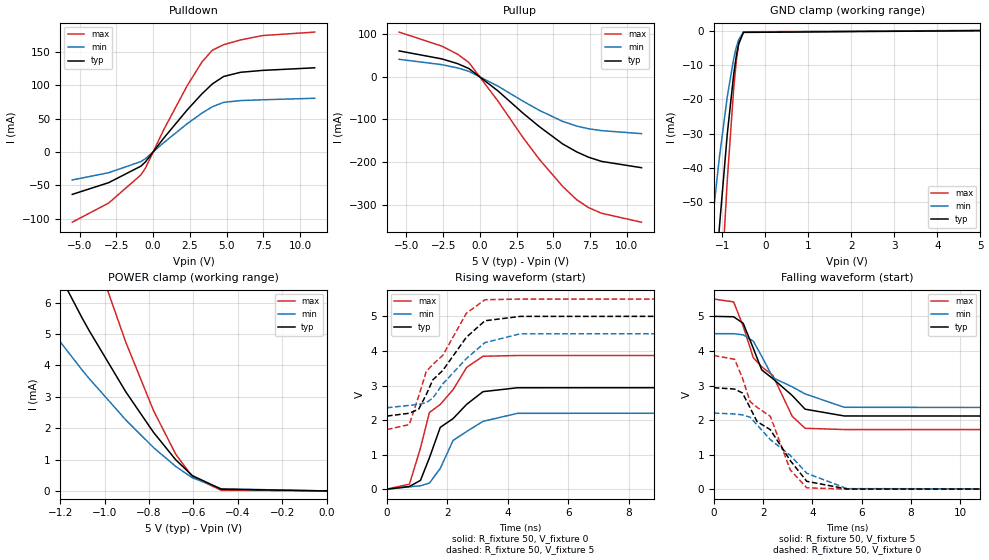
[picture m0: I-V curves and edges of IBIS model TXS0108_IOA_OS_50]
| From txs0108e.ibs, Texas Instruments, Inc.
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[Model]   TXS0108_IOA_OS_50
Model_type  I/O
Vinl=1.35
Vinh=3.85
Enable   Active-Low
Vref =   0
Rref =   1000000
Cref =   15p
Vmeas =   2.5
| variable   typ   min   max
C_comp   4.98pF   4.31pF   5.51pF
| C_pullup   4.44pF   3.65pF   5.60pF
| C_pulldown   5.24pF   4.78pF   5.57pF
| C_tri-state   4.98pF   4.31pF   5.51pF
[Temperature Range]   40   100   -40
| Ambient temperature   25   85   -40
[Voltage range]   5   4.5   5.5
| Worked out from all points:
|   slope of the pulldown table from 0 to 0.75 V, typ, clamps not added: 34.9 ohm
|   slope of the pullup table from 0 to 0.75 V, typ, clamps not added: 36.8 ohm
|   GND clamp passes 1 mA (typ) near -0.54 V on its own axis
|   POWER clamp passes 1 mA (typ) near -0.68 V on its own axis
|   rising waveform, R_fixture 50, V_fixture 0: 20-80 % time 1.24ns typ, 1.15ns min, 1.3ns max; typ from 0.002 V to 2.94 V
|   falling waveform, R_fixture 50, V_fixture 5: 20-80 % time 1.76ns typ, 1.85ns min, 1.74ns max; typ from 5 V to 2.12 V
|   rising waveform, R_fixture 50, V_fixture 5: 20-80 % time 1.37ns typ, 1.32ns min, 1.37ns max; typ from 2.12 V to 5 V
|   falling waveform, R_fixture 50, V_fixture 0: 20-80 % time 1.84ns typ, 1.97ns min, 1.75ns max; typ from 2.94 V to 0.002 V
[GND Clamp]
| TXS0108_IOA_OS_50
|   Voltage   I(typ)   I(min)   I(max)
-5.5V     -1.162A    -886.7mA   -1.457A
-1.485V   -135mA     -89.32mA   -194.3mA
-1.435V   -124.8mA   -82.28mA   -180.2mA
-1.23V    -85.21mA   -55.46mA   -124.7mA
-1.09V    -60.8mA    -39.25mA   -89.36mA
-1.065V   -56.7mA    -36.55mA   -83.34mA
-885mV    -30.02mA   -19.18mA   -43.38mA
-735mV    -12.53mA   -8.039mA   -16.57mA
-675mV    -7.294mA   -4.78mA    -8.768mA
-620mV    -3.741mA   -2.566mA   -3.881mA
-510mV    -503.4uA   -413.9uA   -323.1uA
5V        729.6pA    105.6uA    184.2pA
[POWER Clamp]
| TXS0108_IOA_OS_50
|   Voltage   I(typ)   I(min)   I(max)
-5.5V     90.64mA    62.18mA    150.4mA
-1.575V   12.3mA     8.412mA    20.42mA
-1.54V    11.75mA    8.047mA    19.49mA
-1.31V    8.334mA    5.751mA    13.61mA
-1.1V     5.493mA    3.841mA    8.726mA
-1.07V    5.113mA    3.585mA    8.074mA
-905mV    3.161mA    2.264mA    4.744mA
-780mV    1.867mA    1.382mA    2.561mA
-680mV    992.7uA    780.1uA    1.172mA
-605mV    486.5uA    418.6uA    452uA
-475mV    55.47uA    68.05uA    20.74uA
0V        0A         0A         0A
[Pulldown]
| TXS0108_IOA_OS_50
|   Voltage   I(typ)   I(min)   I(max)
-5.5V     -63.78mA   -42.12mA   -105.5mA
-3.02V    -46.14mA   -31.22mA   -76.72mA
-825mV    -21.34mA   -14.5mA    -34.47mA
-520mV    -15.06mA   -10.15mA   -24.4mA
715mV     20.4mA     13.71mA    32.88mA
2.325V    63.05mA    42.33mA    99.5mA
3.325V    87.1mA     58.2mA     134.8mA
4.03V     101.9mA    67.66mA    152.6mA
4.805V    113.2mA    74.38mA    160.9mA
5.965V    119.5mA    77.04mA    168.1mA
7.45V     122.3mA    78.2mA     174.6mA
11V       126.2mA    80.47mA    179.8mA
[Pullup]
| TXS0108_IOA_OS_50
|   Voltage   I(typ)   I(min)   I(max)
-5.5V     60.23mA    40.59mA    104.3mA
-2.605V   41.71mA    28.15mA    71.68mA
-1.52V    30.52mA    20.47mA    52.64mA
-745mV    18.91mA    12.58mA    32.97mA
1.24V     -33.61mA   -22.41mA   -57.58mA
2.92V     -85.01mA   -57.05mA   -141.8mA
4.035V    -116.6mA   -78.52mA   -193mA
5.635V    -157.4mA   -104.7mA   -256.8mA
6.595V    -176.1mA   -115.6mA   -288.1mA
7.395V    -188.5mA   -121.9mA   -306.4mA
8.29V     -198.3mA   -126.3mA   -319.7mA
11V       -213mA     -133.3mA   -340.5mA
[Ramp]
| TXS0108_IOA_OS_50
| variable   typ   min   max
dV/dt_r   1.76/1.25E-09   1.32/1.15E-09   2.32/1.30E-09
dV/dt_f   1.73/1.76E-09   1.29/1.86E-09   2.26/1.74E-09
R_load = 50
[Rising Waveform]
| TXS0108_IOA_OS_50
R_fixture =   50
C_fixture =   0
L_fixture =   0
V_fixture =   0
V_fixture_min = 0
V_fixture_max = 0
|   Time   V(typ)   V(min)   V(max)
0s        2.415mV    1.849mV    3.091mV
745ps     78.76mV    69.8mV     147.1mV
1.11ns    257.2mV    99.24mV    1.193V
1.405ns   906.8mV    177.7mV    2.22V
1.765ns   1.79V      602.8mV    2.452V
2.19ns    2.043V     1.412V     2.881V
2.64ns    2.456V     1.67V      3.525V
3.18ns    2.822V     1.964V     3.846V
4.325ns   2.935V     2.195V     3.868V
19.92ns   2.937V     2.203V     3.868V
[Falling Waveform]
| TXS0108_IOA_OS_50
R_fixture =   50
C_fixture =   0
L_fixture =   0
V_fixture =   5
V_fixture_min = 4.5
V_fixture_max = 5.5
|   Time   V(typ)   V(min)   V(max)
0s        5V         4.5V       5.5V
805ps     4.988V     4.498V     5.418V
1.195ns   4.798V     4.465V     4.713V
1.605ns   4.074V     4.283V     3.803V
1.945ns   3.452V     3.845V     3.542V
2.4ns     3.195V     3.225V     3.288V
3.18ns    2.712V     2.963V     2.112V
3.705ns   2.315V     2.757V     1.763V
5.295ns   2.119V     2.37V      1.726V
19.92ns   2.116V     2.357V     1.726V
[Rising Waveform]
| TXS0108_IOA_OS_50
R_fixture =   50
C_fixture =   0
L_fixture =   0
V_fixture =   5
V_fixture_min = 4.5
V_fixture_max = 5.5
|   Time   V(typ)   V(min)   V(max)
0s        2.116V     2.357V     1.726V
740ps     2.198V     2.425V     1.871V
1.05ns    2.315V     2.455V     2.689V
1.3ns     2.734V     2.502V     3.402V
1.52ns    3.165V     2.637V     3.611V
1.85ns    3.437V     3.048V     3.874V
2.63ns    4.396V     3.779V     5.091V
3.245ns   4.873V     4.242V     5.481V
4.415ns   4.999V     4.495V     5.5V
19.92ns   5V         4.5V       5.5V
[Falling Waveform]
| TXS0108_IOA_OS_50
R_fixture =   50
C_fixture =   0
L_fixture =   0
V_fixture =   0
V_fixture_min = 0
V_fixture_max = 0
|   Time   V(typ)   V(min)   V(max)
0s        2.937V     2.203V     3.868V
845ps     2.897V     2.176V     3.759V
1.165ns   2.783V     2.15V      3.212V
1.47ns    2.362V     2.084V     2.538V
1.755ns   1.957V     1.862V     2.37V
2.295ns   1.722V     1.435V     2.108V
3.105ns   827.4mV    978.5mV    556.9mV
3.775ns   228.6mV    460.9mV    40.84mV
5.41ns    6.523mV    17.31mV    3.988mV
19.92ns   2.417mV    1.85mV     3.092mV
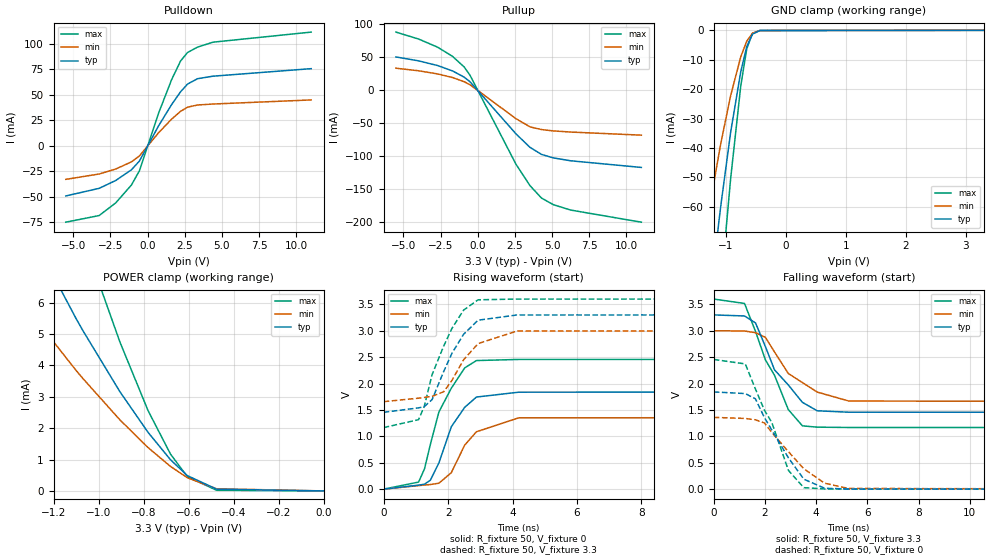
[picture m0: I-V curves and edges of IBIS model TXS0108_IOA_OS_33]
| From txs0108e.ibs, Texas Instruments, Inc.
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[Model]   TXS0108_IOA_OS_33
Model_type  I/O
Vinl=0.8
Vinh=2.0
Enable   Active-Low
Vref =   0
Rref =   1000000
Cref =   15p
Vmeas =   1.65
| variable   typ   min   max
C_comp   5.18pF   4.53pF   5.58pF
| C_pullup   4.70pF   3.82pF   5.92pF
| C_pulldown   5.52pF   5.09pF   5.94pF
| C_tri-state   5.18pF   4.53pF   5.58pF
[Temperature Range]   40   100   -40
| Ambient temperature   25   85   -40
[Voltage range]   3.3   3   3.6
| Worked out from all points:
|   slope of the pulldown table from 0 to 0.495 V, typ, clamps not added: 36.9 ohm
|   slope of the pullup table from 0 to 0.495 V, typ, clamps not added: 40 ohm
|   GND clamp passes 1 mA (typ) near -0.54 V on its own axis
|   POWER clamp passes 1 mA (typ) near -0.68 V on its own axis
|   rising waveform, R_fixture 50, V_fixture 0: 20-80 % time 779ps typ, 824ps min, 824ps max; typ from 0.002 V to 1.84 V
|   falling waveform, R_fixture 50, V_fixture 3.3: 20-80 % time 1.29ns typ, 1.53ns min, 1.23ns max; typ from 3.3 V to 1.46 V
|   rising waveform, R_fixture 50, V_fixture 3.3: 20-80 % time 869ps typ, 896ps min, 878ps max; typ from 1.46 V to 3.3 V
|   falling waveform, R_fixture 50, V_fixture 0: 20-80 % time 1.32ns typ, 1.54ns min, 1.21ns max; typ from 1.84 V to 0.002 V
[GND Clamp]
| TXS0108_IOA_OS_33
|   Voltage   I(typ)   I(min)   I(max)
-5.5V     -1.162A    -886.7mA   -1.457A
-1.485V   -135mA     -89.32mA   -194.3mA
-1.285V   -95.42mA   -62.32mA   -139.2mA
-1.24V    -87.04mA   -56.68mA   -127.3mA
-1.1V     -62.46mA   -40.34mA   -91.79mA
-1.08V    -59.15mA   -38.16mA   -86.94mA
-920mV    -34.79mA   -22.26mA   -50.61mA
-750mV    -14.03mA   -8.977mA   -18.85mA
-650mV    -5.516mA   -3.676mA   -6.254mA
-555mV    -1.279mA   -963.7uA   -1.023mA
-430mV    -72.15uA   -72.69uA   -27.98uA
3.3V      399.8pA    1.399uA    111.4pA
[POWER Clamp]
| TXS0108_IOA_OS_33
|   Voltage   I(typ)   I(min)   I(max)
-5.5V     90.64mA    62.18mA    150.4mA
-1.575V   12.3mA     8.412mA    20.42mA
-1.54V    11.75mA    8.047mA    19.49mA
-1.31V    8.334mA    5.751mA    13.61mA
-1.1V     5.493mA    3.841mA    8.726mA
-1.07V    5.113mA    3.585mA    8.074mA
-905mV    3.161mA    2.264mA    4.744mA
-780mV    1.867mA    1.382mA    2.561mA
-680mV    992.7uA    780.1uA    1.172mA
-605mV    486.5uA    418.6uA    452uA
-475mV    55.47uA    68.05uA    20.74uA
0V        0A         0A         0A
[Pulldown]
| TXS0108_IOA_OS_33
|   Voltage   I(typ)   I(min)   I(max)
-5.5V     -49.2mA    -32.91mA   -74.97mA
-3.255V   -41.72mA   -27.65mA   -68.43mA
-2.145V   -34.02mA   -22.77mA   -56.02mA
-1.09V    -23.56mA   -15.75mA   -38.51mA
-550mV    -14.93mA   -9.869mA   -24.48mA
735mV     19.58mA    12.8mA     32.01mA
1.615V    40.54mA    26.25mA    65.03mA
2.215V    53.05mA    33.87mA    83.29mA
2.68V     60.63mA    37.94mA    91.63mA
3.355V    65.93mA    40.11mA    96.94mA
4.395V    68.4mA     41.06mA    101.8mA
11V       75.8mA     45.09mA    111.7mA
[Pullup]
| TXS0108_IOA_OS_33
|   Voltage   I(typ)   I(min)   I(max)
-5.5V     50.72mA    33.63mA    88.38mA
-3.965V   44.75mA    29.7mA     77.77mA
-2.695V   37.64mA    24.95mA    65.49mA
-1.685V   29.4mA     19.4mA     51.39mA
-910mV    20.07mA    13.14mA    35.46mA
-520mV    13.1mA     8.58mA     22.93mA
2.57V     -65.87mA   -42.88mA   -111.9mA
3.51V     -86.32mA   -55.25mA   -144.3mA
4.285V    -97.02mA   -59.38mA   -163.2mA
5.08V     -102.3mA   -61.42mA   -173.2mA
6.245V    -106.7mA   -63.15mA   -181.4mA
11V       -116.8mA   -67.86mA   -199.8mA
[Ramp]
| TXS0108_IOA_OS_33
| variable   typ   min   max
dV/dt_r   1.10/7.83E-10   0.82/8.25E-10   1.47/8.28E-10
dV/dt_f   1.11/1.29E-09   0.81/1.53E-09   1.46/1.23E-09
R_load = 50
[Rising Waveform]
| TXS0108_IOA_OS_33
R_fixture =   50
C_fixture =   0
L_fixture =   0
V_fixture =   0
V_fixture_min = 0
V_fixture_max = 0
|   Time   V(typ)   V(min)   V(max)
0s        1.639mV    1.274mV    2.07mV
1.085ns   77.44mV    68.86mV    135.6mV
1.27ns    96.58mV    79.28mV    389.8mV
1.45ns    170.7mV    89.07mV    848.2mV
1.715ns   498.5mV    113.8mV    1.463V
2.1ns     1.183V     313.4mV    1.912V
2.515ns   1.55V      834.5mV    2.296V
2.88ns    1.745V     1.088V     2.436V
4.19ns    1.837V     1.351V     2.457V
19.95ns   1.842V     1.36V      2.457V
[Falling Waveform]
| TXS0108_IOA_OS_33
R_fixture =   50
C_fixture =   0
L_fixture =   0
V_fixture =   3.3
V_fixture_min = 3
V_fixture_max = 3.6
|   Time   V(typ)   V(min)   V(max)
0s        3.3V       3V         3.6V
1.2ns     3.28V      2.996V     3.517V
1.63ns    3.148V     2.963V     2.987V
2.015ns   2.701V     2.876V     2.45V
2.37ns    2.261V     2.599V     2.158V
2.91ns    1.974V     2.191V     1.508V
3.46ns    1.645V     2.019V     1.2V
4.04ns    1.485V     1.839V     1.175V
5.27ns    1.458V     1.67V      1.169V
19.95ns   1.456V     1.658V     1.167V
[Rising Waveform]
| TXS0108_IOA_OS_33
R_fixture =   50
C_fixture =   0
L_fixture =   0
V_fixture =   3.3
V_fixture_min = 3
V_fixture_max = 3.6
|   Time   V(typ)   V(min)   V(max)
0s        1.456V     1.658V     1.167V
1.085ns   1.54V      1.724V     1.317V
1.26ns    1.564V     1.737V     1.568V
1.505ns   1.698V     1.758V     2.172V
1.865ns   2.231V     1.846V     2.712V
2.12ns    2.573V     2.061V     3.045V
2.48ns    2.932V     2.449V     3.39V
2.93ns    3.2V       2.757V     3.586V
4.14ns    3.299V     2.995V     3.6V
19.95ns   3.3V       3V         3.6V
[Falling Waveform]
| TXS0108_IOA_OS_33
R_fixture =   50
C_fixture =   0
L_fixture =   0
V_fixture =   0
V_fixture_min = 0
V_fixture_max = 0
|   Time   V(typ)   V(min)   V(max)
0s        1.842V     1.36V      2.457V
1.23ns    1.811V     1.34V      2.372V
1.625ns   1.712V     1.314V     1.899V
1.98ns    1.354V     1.254V     1.493V
2.265ns   1.122V     1.075V     1.265V
2.915ns   594.1mV    710.6mV    355.7mV
3.515ns   190.6mV    387.4mV    29.92mV
4.33ns    17.96mV    113.2mV    5.557mV
5.26ns    5.019mV    14.81mV    2.72mV
19.95ns   1.64mV     1.275mV    2.071mV
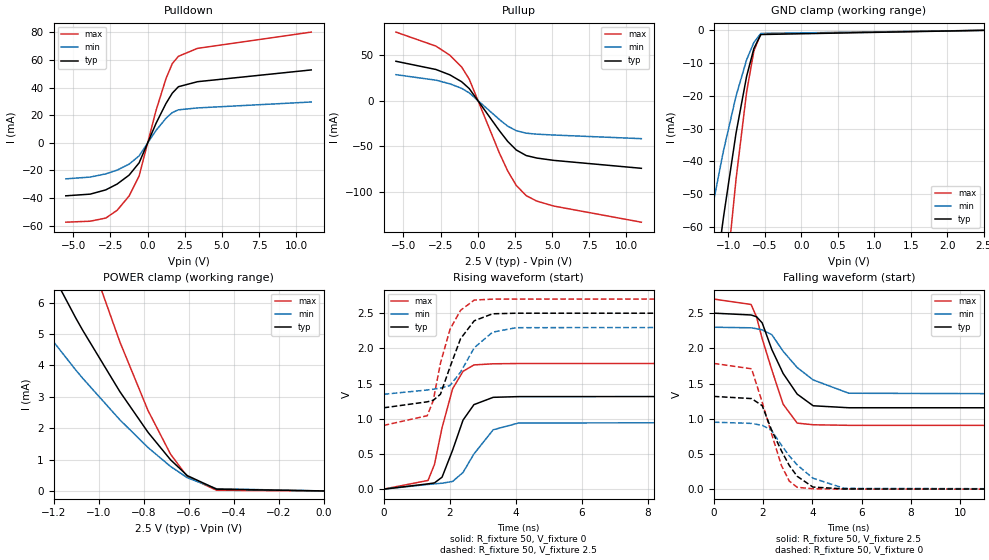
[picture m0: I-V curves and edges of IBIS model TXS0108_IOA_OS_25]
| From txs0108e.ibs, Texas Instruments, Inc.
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[Model]   TXS0108_IOA_OS_25
Model_type  I/O
Vinl=0.7
Vinh=1.7
Enable   Active-Low
Vref =   0
Rref =   1000000
Cref =   15p
Vmeas =   1.25
| variable   typ   min   max
C_comp   5.32pF   4.63pF   5.62pF
| C_pullup   5.03pF   3.89pF   6.32pF
| C_pulldown   5.75pF   5.36pF   6.43pF
| C_tri-state   5.32pF   4.63pF   5.62pF
[Temperature Range]   40   100   -40
| Ambient temperature   25   85   -40
[Voltage range]   2.5   2.3   2.7
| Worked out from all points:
|   slope of the pulldown table from 0 to 0.375 V, typ, clamps not added: 39.3 ohm
|   slope of the pullup table from 0 to 0.375 V, typ, clamps not added: 43.7 ohm
|   GND clamp passes 1 mA (typ) near -0.54 V on its own axis
|   POWER clamp passes 1 mA (typ) near -0.68 V on its own axis
|   rising waveform, R_fixture 50, V_fixture 0: 20-80 % time 608ps typ, 792ps min, 549ps max; typ from 0.001 V to 1.32 V
|   falling waveform, R_fixture 50, V_fixture 2.5: 20-80 % time 1.1ns typ, 1.55ns min, 932ps max; typ from 2.5 V to 1.16 V
|   rising waveform, R_fixture 50, V_fixture 2.5: 20-80 % time 643ps typ, 761ps min, 572ps max; typ from 1.16 V to 2.5 V
|   falling waveform, R_fixture 50, V_fixture 0: 20-80 % time 1.08ns typ, 1.38ns min, 888ps max; typ from 1.32 V to 0.001 V
[GND Clamp]
| TXS0108_IOA_OS_25
|   Voltage   I(typ)   I(min)   I(max)
-5.5V     -1.162A    -886.7mA   -1.457A
-1.475V   -132.9mA   -87.89mA   -191.4mA
-1.425V   -122.7mA   -80.89mA   -177.4mA
-1.235V   -86.12mA   -56.07mA   -126mA
-1.21V    -81.58mA   -53.03mA   -119.5mA
-1.085V   -59.97mA   -38.7mA    -88.15mA
-1.065V   -56.7mA    -36.55mA   -83.34mA
-895mV    -31.36mA   -20.04mA   -45.42mA
-750mV    -14.03mA   -8.977mA   -18.85mA
-650mV    -5.516mA   -3.676mA   -6.254mA
-555mV    -1.279mA   -963.7uA   -1.023mA
2.5V      289.1pA    97.72nA    83.51pA
[POWER Clamp]
| TXS0108_IOA_OS_25
|   Voltage   I(typ)   I(min)   I(max)
-5.5V     90.64mA    62.18mA    150.4mA
-1.575V   12.3mA     8.412mA    20.42mA
-1.54V    11.75mA    8.047mA    19.49mA
-1.31V    8.334mA    5.751mA    13.61mA
-1.1V     5.493mA    3.841mA    8.726mA
-1.07V    5.113mA    3.585mA    8.074mA
-905mV    3.161mA    2.264mA    4.744mA
-780mV    1.867mA    1.382mA    2.561mA
-680mV    992.7uA    780.1uA    1.172mA
-605mV    486.5uA    418.6uA    452uA
-475mV    55.47uA    68.05uA    20.74uA
0V        0A         0A         0A
[Pulldown]
| TXS0108_IOA_OS_25
|   Voltage   I(typ)   I(min)   I(max)
-5.5V     -38.38mA   -26.09mA   -57.48mA
-3.86V    -37.17mA   -24.81mA   -56.77mA
-2.81V    -34.07mA   -22.49mA   -54.48mA
-2.05V    -29.87mA   -19.76mA   -48.88mA
-1.245V   -23.41mA   -15.47mA   -38.52mA
-570mV    -14.49mA   -9.437mA   -23.98mA
565mV     14.07mA    8.957mA    23.39mA
1.24V     28.57mA    17.84mA    46.62mA
1.66V     35.97mA    21.9mA     57.39mA
2.07V     40.62mA    23.88mA    62.63mA
3.355V    44.26mA    25.26mA    68.41mA
11V       52.78mA    29.56mA    80.18mA
[Pullup]
| TXS0108_IOA_OS_25
|   Voltage   I(typ)   I(min)   I(max)
-5.5V     42.97mA    28.35mA    74.8mA
-2.81V    34mA       22.34mA    59.5mA
-1.87V    28.12mA    18.39mA    49.54mA
-1.085V   20.65mA    13.4mA     36.8mA
-575mV    13.25mA    8.569mA    23.58mA
1.455V    -32.73mA   -20.58mA   -57.12mA
2.02V     -44.58mA   -27.9mA    -76.88mA
2.59V     -53.81mA   -32.77mA   -92.47mA
3.255V    -59.87mA   -35.47mA   -103.6mA
3.97V     -62.63mA   -36.57mA   -109.6mA
5.11V     -65.15mA   -37.5mA    -115mA
11V       -73.81mA   -41.47mA   -132.6mA
[Ramp]
| TXS0108_IOA_OS_25
| variable   typ   min   max
dV/dt_r   0.79/6.09E-10   0.57/7.96E-10   1.07/5.55E-10
dV/dt_f   0.81/1.11E-09   0.57/1.55E-09   1.08/9.35E-10
R_load = 50
[Rising Waveform]
| TXS0108_IOA_OS_25
R_fixture =   50
C_fixture =   0
L_fixture =   0
V_fixture =   0
V_fixture_min = 0
V_fixture_max = 0
|   Time   V(typ)   V(min)   V(max)
0s        1.279mV    1.009mV    1.594mV
1.345ns   76.21mV    67.95mV    125mV
1.54ns    90.23mV    76.32mV    352.8mV
1.77ns    171.5mV    85.44mV    875.2mV
2.09ns    555.6mV    111mV      1.427V
2.405ns   981.5mV    238.2mV    1.674V
2.735ns   1.201V     500.6mV    1.765V
3.32ns    1.305V     844.6mV    1.781V
4.09ns    1.315V     940.3mV    1.785V
19.95ns   1.318V     951.8mV    1.786V
[Falling Waveform]
| TXS0108_IOA_OS_25
R_fixture =   50
C_fixture =   0
L_fixture =   0
V_fixture =   2.5
V_fixture_min = 2.3
V_fixture_max = 2.7
|   Time   V(typ)   V(min)   V(max)
0s        2.5V       2.3V       2.7V
1.515ns   2.474V     2.292V     2.623V
1.735ns   2.449V     2.279V     2.447V
1.965ns   2.362V     2.262V     2.138V
2.355ns   1.985V     2.195V     1.696V
2.815ns   1.644V     1.959V     1.208V
3.385ns   1.351V     1.728V     939.2mV
4.035ns   1.185V     1.552V     915.1mV
5.48ns    1.157V     1.363V     907.4mV
19.95ns   1.156V     1.348V     905.8mV
[Rising Waveform]
| TXS0108_IOA_OS_25
R_fixture =   50
C_fixture =   0
L_fixture =   0
V_fixture =   2.5
V_fixture_min = 2.3
V_fixture_max = 2.7
|   Time   V(typ)   V(min)   V(max)
0s        1.156V     1.348V     905.8mV
1.32ns    1.241V     1.409V     1.044V
1.5ns     1.262V     1.42V      1.254V
1.72ns    1.348V     1.436V     1.788V
2.01ns    1.734V     1.473V     2.27V
2.33ns    2.137V     1.662V     2.54V
2.745ns   2.392V     2.009V     2.686V
3.3ns     2.491V     2.23V      2.699V
4.02ns    2.499V     2.294V     2.7V
19.95ns   2.5V       2.3V       2.7V
[Falling Waveform]
| TXS0108_IOA_OS_25
R_fixture =   50
C_fixture =   0
L_fixture =   0
V_fixture =   0
V_fixture_min = 0
V_fixture_max = 0
|   Time   V(typ)   V(min)   V(max)
0s        1.318V     951.8mV    1.786V
1.535ns   1.287V     934.4mV    1.71V
1.965ns   1.187V     907.3mV    1.236V
2.33ns    854.7mV    842.7mV    807.1mV
2.745ns   545.9mV    627.4mV    337.6mV
3.065ns   337.7mV    474.3mV    116mV
3.385ns   184.1mV    345.3mV    27.82mV
4.025ns   30.96mV    156.6mV    6.487mV
5.295ns   4.435mV    12.47mV    2.133mV
19.95ns   1.279mV    1.01mV     1.595mV
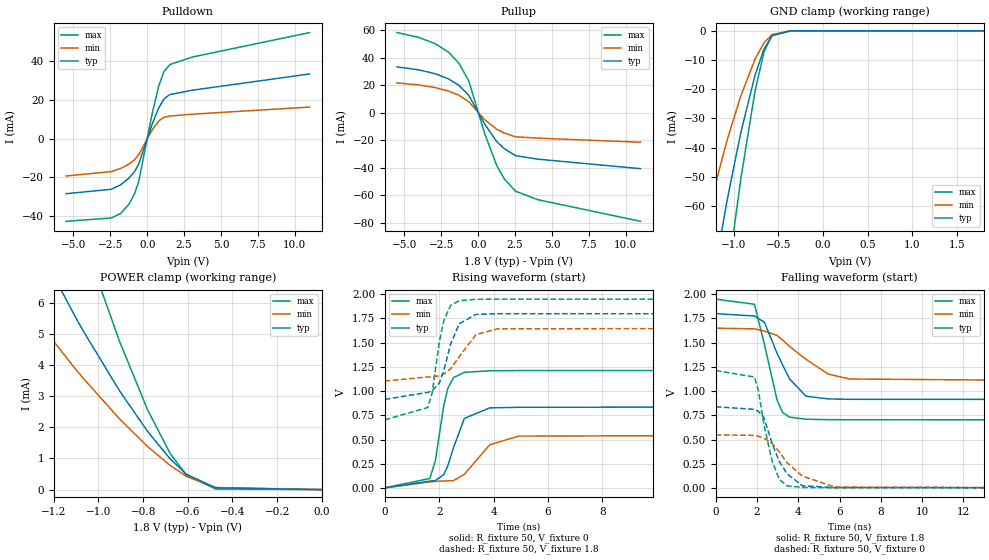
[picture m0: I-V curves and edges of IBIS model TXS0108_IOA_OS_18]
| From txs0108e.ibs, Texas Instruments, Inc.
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[Model]   TXS0108_IOA_OS_18
Model_type  I/O
Vinl=0.5775
Vinh=1.2675
Enable   Active-Low
Vref =   0
Rref =   1000000
Cref =   15p
Vmeas =   0.9
| variable   typ   min   max
C_comp   5.46pF   4.75pF   5.78pF
| C_pullup   5.54pF   4.12pF   6.50pF
| C_pulldown   6.05pF   5.46pF   6.99pF
| C_tri-state   5.46pF   4.75pF   5.78pF
[Temperature Range]   40   100   -40
| Ambient temperature   25   85   -40
[Voltage range]   1.8   1.65   1.95
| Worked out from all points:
|   slope of the pulldown table from 0 to 0.27 V, typ, clamps not added: 44.3 ohm
|   slope of the pullup table from 0 to 0.27 V, typ, clamps not added: 51.5 ohm
|   GND clamp passes 1 mA (typ) near -0.54 V on its own axis
|   POWER clamp passes 1 mA (typ) near -0.68 V on its own axis
|   rising waveform, R_fixture 50, V_fixture 0: 20-80 % time 606ps typ, 1.01ns min, 427ps max; typ from 0.001 V to 0.838 V
|   falling waveform, R_fixture 50, V_fixture 1.8: 20-80 % time 1.12ns typ, 1.96ns min, 765ps max; typ from 1.8 V to 0.914 V
|   rising waveform, R_fixture 50, V_fixture 1.8: 20-80 % time 579ps typ, 829ps min, 421ps max; typ from 0.914 V to 1.8 V
|   falling waveform, R_fixture 50, V_fixture 0: 20-80 % time 939ps typ, 1.46ns min, 679ps max; typ from 0.838 V to 0.001 V
[GND Clamp]
| TXS0108_IOA_OS_18
|   Voltage   I(typ)   I(min)   I(max)
-5.5V     -1.162A    -886.7mA   -1.457A
-1.485V   -135mA     -89.32mA   -194.3mA
-1.435V   -124.8mA   -82.28mA   -180.2mA
-1.225V   -84.3mA    -54.85mA   -123.4mA
-1.085V   -59.97mA   -38.7mA    -88.15mA
-1.065V   -56.7mA    -36.55mA   -83.34mA
-920mV    -34.79mA   -22.26mA   -50.61mA
-760mV    -15.06mA   -9.626mA   -20.43mA
-660mV    -6.196mA   -4.099mA   -7.202mA
-570mV    -1.688mA   -1.24mA    -1.444mA
-365mV    -12.15uA   -15.38uA   -2.755uA
1.8V      209pA      23.51nA    59.06pA
[POWER Clamp]
| TXS0108_IOA_OS_18
|   Voltage   I(typ)   I(min)   I(max)
-5.5V     90.64mA    62.18mA    150.4mA
-1.575V   12.3mA     8.412mA    20.42mA
-1.54V    11.75mA    8.047mA    19.49mA
-1.31V    8.334mA    5.751mA    13.61mA
-1.1V     5.493mA    3.841mA    8.726mA
-1.07V    5.113mA    3.585mA    8.074mA
-905mV    3.161mA    2.264mA    4.744mA
-780mV    1.867mA    1.382mA    2.561mA
-680mV    992.7uA    780.1uA    1.172mA
-605mV    486.5uA    418.6uA    452uA
-475mV    55.47uA    68.05uA    20.74uA
0V        0A         0A         0A
[Pulldown]
| TXS0108_IOA_OS_18
|   Voltage   I(typ)   I(min)   I(max)
-5.5V     -28.43mA   -19.26mA   -42.65mA
-2.425V   -26.12mA   -17.02mA   -40.94mA
-1.795V   -23.8mA    -15.4mA    -38.63mA
-1.245V   -20.46mA   -13.17mA   -33.93mA
-855mV    -17.03mA   -10.89mA   -28.4mA
-575mV    -13.17mA   -8.336mA   -22.18mA
325mV     7.229mA    4.354mA    12.46mA
790mV     15.97mA    9.139mA    27.36mA
1.14V     20.45mA    11.03mA    34.57mA
1.535V    22.71mA    11.65mA    38.18mA
3.05V     24.95mA    12.58mA    42.06mA
11V       33.34mA    16.28mA    54.69mA
[Pullup]
| TXS0108_IOA_OS_18
|   Voltage   I(typ)   I(min)   I(max)
-5.5V     33.3mA     21.65mA    58.23mA
-4.06V    31.21mA    20.21mA    54.85mA
-2.92V    28.35mA    18.27mA    50.19mA
-2.005V   24.56mA    15.74mA    43.93mA
-1.3V     19.87mA    12.66mA    35.91mA
-630mV    12.55mA    7.934mA    22.85mA
430mV     -8.16mA    -5.025mA   -14.85mA
1.265V    -21.13mA   -12.09mA   -38.67mA
1.775V    -26.2mA    -14.78mA   -48.17mA
2.53V     -31.21mA   -17.53mA   -57.04mA
4.03V     -33.73mA   -18.47mA   -63.18mA
11V       -40.66mA   -21.47mA   -78.9mA
[Ramp]
| TXS0108_IOA_OS_18
| variable   typ   min   max
dV/dt_r   0.50/6.13E-10   0.33/1.01E-09   0.73/4.32E-10
dV/dt_f   0.53/1.12E-09   0.33/1.96E-09   0.75/7.66E-10
R_load = 50
[Rising Waveform]
| TXS0108_IOA_OS_18
R_fixture =   50
C_fixture =   0
L_fixture =   0
V_fixture =   0
V_fixture_min = 0
V_fixture_max = 0
|   Time   V(typ)   V(min)   V(max)
0s        969.5uV    766.9uV    1.205mV
1.655ns   70.4mV     61.67mV    97.38mV
1.86ns    76.46mV    66.92mV    280.3mV
2.165ns   136.8mV    71.67mV    844.1mV
2.315ns   227mV      72.56mV    1.026V
2.525ns   414.1mV    75.81mV    1.139V
2.925ns   717.8mV    139.6mV    1.194V
3.86ns    826.8mV    446.2mV    1.21V
4.93ns    832.8mV    535.1mV    1.212V
19.95ns   838.2mV    547.6mV    1.213V
[Falling Waveform]
| TXS0108_IOA_OS_18
R_fixture =   50
C_fixture =   0
L_fixture =   0
V_fixture =   1.8
V_fixture_min = 1.65
V_fixture_max = 1.95
|   Time   V(typ)   V(min)   V(max)
0s        1.8V       1.65V      1.95V
1.87ns    1.776V     1.643V     1.897V
2.355ns   1.711V     1.62V      1.483V
2.965ns   1.393V     1.575V     911.7mV
3.235ns   1.272V     1.528V     780mV
3.57ns    1.127V     1.462V     731.2mV
4.37ns    947.7mV    1.328V     709.6mV
5.45ns    919.3mV    1.176V     705.1mV
6.495ns   915.4mV    1.125V     704.5mV
19.95ns   914.1mV    1.104V     703.4mV
[Rising Waveform]
| TXS0108_IOA_OS_18
R_fixture =   50
C_fixture =   0
L_fixture =   0
V_fixture =   1.8
V_fixture_min = 1.65
V_fixture_max = 1.95
|   Time   V(typ)   V(min)   V(max)
0s        914.1mV    1.104V     703.4mV
1.58ns    987.2mV    1.146V     830.3mV
1.745ns   1.004V     1.148V     985.6mV
2.005ns   1.083V     1.158V     1.51V
2.175ns   1.219V     1.177V     1.733V
2.425ns   1.49V      1.232V     1.887V
2.74ns    1.696V     1.357V     1.934V
3.355ns   1.792V     1.583V     1.948V
4.14ns    1.799V     1.643V     1.95V
19.95ns   1.8V       1.65V      1.95V
[Falling Waveform]
| TXS0108_IOA_OS_18
R_fixture =   50
C_fixture =   0
L_fixture =   0
V_fixture =   0
V_fixture_min = 0
V_fixture_max = 0
|   Time   V(typ)   V(min)   V(max)
0s        838.3mV    547.6mV    1.213V
1.87ns    811.5mV    543.1mV    1.146V
2.07ns    789.5mV    533.4mV    1V
2.33ns    727.1mV    511.8mV    655.9mV
2.725ns   460.3mV    459.6mV    278.5mV
3.08ns    273.3mV    370.2mV    88.19mV
3.445ns   148.6mV    262.5mV    21.63mV
4.19ns    22.91mV    123.4mV    5.242mV
5.75ns    3.308mV    9.794mV    1.599mV
19.95ns   969.7uV    767.9uV    1.205mV
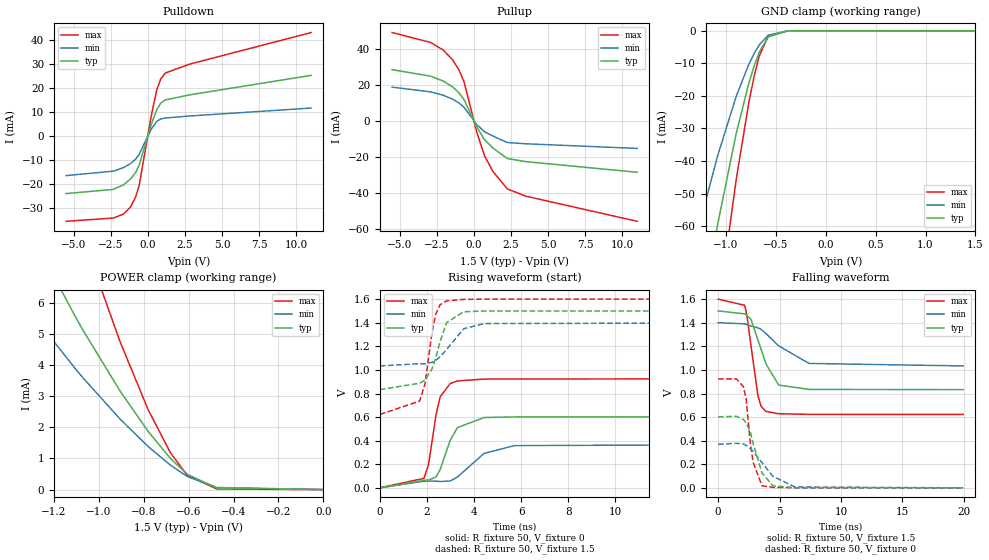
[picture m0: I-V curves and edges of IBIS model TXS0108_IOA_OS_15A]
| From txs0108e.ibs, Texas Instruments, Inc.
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[Model]   TXS0108_IOA_OS_15A
Model_type  I/O
Vinl=0.15
Vinh=1.4
Enable   Active-Low
Vref =   0
Rref =   1000000
Cref =   15p
Vmeas =   0.75
| variable   typ   min   max
C_comp   5.53pF   4.82pF   5.86pF
| C_pullup   5.82pF   4.31pF   6.75pF
| C_pulldown   6.22pF   5.50pF   7.19pF
| C_tri-state   5.53pF   4.82pF   5.86pF
[Temperature Range]   40   100   -40
| Ambient temperature   25   85   -40
[Voltage range]   1.5   1.4   1.6
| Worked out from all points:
|   slope of the pulldown table from 0 to 0.225 V, typ, clamps not added: 48.9 ohm
|   slope of the pullup table from 0 to 0.225 V, typ, clamps not added: 59 ohm
|   GND clamp passes 1 mA (typ) near -0.54 V on its own axis
|   POWER clamp passes 1 mA (typ) near -0.68 V on its own axis
|   rising waveform, R_fixture 50, V_fixture 0: 20-80 % time 708ps typ, 1.29ns min, 457ps max; typ from 0.001 V to 0.602 V
|   falling waveform, R_fixture 50, V_fixture 1.5: 20-80 % time 1.31ns typ, 2.31ns min, 750ps max; typ from 1.5 V to 0.833 V
|   rising waveform, R_fixture 50, V_fixture 1.5: 20-80 % time 647ps typ, 886ps min, 441ps max; typ from 0.833 V to 1.5 V
|   falling waveform, R_fixture 50, V_fixture 0: 20-80 % time 1ns typ, 1.76ns min, 616ps max; typ from 0.602 V to 0.001 V
[GND Clamp]
| TXS0108_IOA_OS_15A
|   Voltage   I(typ)   I(min)   I(max)
-5.5V     -1.162A    -886.7mA   -1.457A
-1.47V    -131.9mA   -87.19mA   -190mA
-1.42V    -121.7mA   -80.21mA   -176mA
-1.24V    -87.04mA   -56.68mA   -127.3mA
-1.08V    -59.15mA   -38.16mA   -86.94mA
-895mV    -31.36mA   -20.04mA   -45.42mA
-770mV    -16.12mA   -10.3mA    -22.07mA
-715mV    -10.65mA   -6.862mA   -13.72mA
-665mV    -6.551mA   -4.319mA   -7.705mA
-575mV    -1.844mA   -1.344mA   -1.612mA
-380mV    -18.61uA   -22.23uA   -4.813uA
1.5V      178.6pA    5.585nA    50.12pA
[POWER Clamp]
| TXS0108_IOA_OS_15A
|   Voltage   I(typ)   I(min)   I(max)
-5.5V     90.64mA    62.18mA    150.4mA
-1.575V   12.3mA     8.412mA    20.42mA
-1.54V    11.75mA    8.047mA    19.49mA
-1.31V    8.334mA    5.751mA    13.61mA
-1.1V     5.493mA    3.841mA    8.726mA
-1.07V    5.113mA    3.585mA    8.074mA
-905mV    3.161mA    2.264mA    4.744mA
-780mV    1.867mA    1.382mA    2.561mA
-680mV    992.7uA    780.1uA    1.172mA
-605mV    486.5uA    418.6uA    452uA
-475mV    55.47uA    68.05uA    20.74uA
0V        0A         0A         0A
[Pulldown]
| TXS0108_IOA_OS_15A
|   Voltage   I(typ)   I(min)   I(max)
-5.5V     -24.12mA   -16.6mA    -35.69mA
-2.325V   -22.36mA   -14.74mA   -34.33mA
-1.64V    -20.5mA    -13.28mA   -32.7mA
-1.165V   -18.06mA   -11.58mA   -29.76mA
-825mV    -15.38mA   -9.784mA   -25.66mA
-575mV    -12.21mA   -7.667mA   -20.64mA
225mV     4.564mA    2.68mA     8.031mA
600mV     10.84mA    6.024mA    19.01mA
875mV     13.67mA    7.085mA    23.84mA
1.18V     15.01mA    7.457mA    26.26mA
2.84V     17.16mA    8.314mA    30.01mA
11V       25.27mA    11.62mA    43.16mA
[Pullup]
| TXS0108_IOA_OS_15A
|   Voltage   I(typ)   I(min)   I(max)
-5.5V     28.3mA     18.62mA    48.86mA
-2.91V    24.7mA     16.02mA    43.4mA
-2.05V    21.98mA    14.13mA    39.14mA
-1.405V   18.64mA    11.89mA    33.59mA
-985mV    15.35mA    9.747mA    27.96mA
-655mV    11.77mA    7.443mA    21.53mA
210mV     -3.572mA   -2.197mA   -6.546mA
725mV     -10.5mA    -6.079mA   -19.47mA
1.29V     -15.12mA   -8.495mA   -28.09mA
2.255V    -20.92mA   -12.05mA   -37.72mA
3.49V     -22.62mA   -12.75mA   -41.75mA
11V       -28.54mA   -15.31mA   -55.69mA
[Ramp]
| TXS0108_IOA_OS_15A
| variable   typ   min   max
dV/dt_r   0.36/7.10E-10   0.22/1.29E-09   0.55/4.60E-10
dV/dt_f   0.40/1.31E-09   0.22/2.31E-09   0.59/7.54E-10
R_load = 50
[Rising Waveform]
| TXS0108_IOA_OS_15A
R_fixture =   50
C_fixture =   0
L_fixture =   0
V_fixture =   0
V_fixture_min = 0
V_fixture_max = 0
|   Time   V(typ)   V(min)   V(max)
0s        840.5uV    675.3uV    1.03mV
1.875ns   64.87mV    57.08mV    81.37mV
2.07ns    67.27mV    58.79mV    200.3mV
2.385ns   92.89mV    57.38mV    617.5mV
2.56ns    155.3mV    54.73mV    771.5mV
2.99ns    405mV      59.01mV    884.9mV
3.295ns   511mV      92.29mV    906.7mV
4.425ns   596.7mV    292.4mV    922.6mV
5.725ns   601.8mV    358.9mV    923.4mV
19.95ns   602.5mV    369.4mV    924.2mV
[Falling Waveform]
| TXS0108_IOA_OS_15A
R_fixture =   50
C_fixture =   0
L_fixture =   0
V_fixture =   1.5
V_fixture_min = 1.4
V_fixture_max = 1.6
|   Time   V(typ)   V(min)   V(max)
0s        1.5V       1.4V       1.6V
2.16ns    1.475V     1.391V     1.548V
2.345ns   1.463V     1.384V     1.461V
2.675ns   1.428V     1.372V     1.205V
3.235ns   1.256V     1.357V     784.8mV
3.495ns   1.176V     1.344V     691.4mV
3.9ns     1.05V      1.308V     648.3mV
4.925ns   871.6mV    1.204V     628.9mV
7.41ns    834.8mV    1.055V     623.4mV
19.95ns   833.2mV    1.034V     623mV
[Rising Waveform]
| TXS0108_IOA_OS_15A
R_fixture =   50
C_fixture =   0
L_fixture =   0
V_fixture =   1.5
V_fixture_min = 1.4
V_fixture_max = 1.6
|   Time   V(typ)   V(min)   V(max)
0s        833.2mV    1.034V     622.8mV
1.69ns    887.5mV    1.053V     735.7mV
1.92ns    914.3mV    1.052V     881.6mV
2.21ns    1.007V     1.064V     1.309V
2.365ns   1.094V     1.08V      1.467V
2.55ns    1.234V     1.109V     1.551V
2.835ns   1.401V     1.174V     1.585V
3.565ns   1.493V     1.349V     1.598V
4.43ns    1.499V     1.393V     1.6V
19.95ns   1.5V       1.4V       1.6V
[Falling Waveform]
| TXS0108_IOA_OS_15A
R_fixture =   50
C_fixture =   0
L_fixture =   0
V_fixture =   0
V_fixture_min = 0
V_fixture_max = 0
|   Time   V(typ)   V(min)   V(max)
0s        602.5mV    369.4mV    924.2mV
1.485ns   607mV      378.4mV    924.9mV
2.065ns   580mV      372.8mV    856.5mV
2.28ns    551.6mV    361.4mV    752.5mV
2.62ns    475.4mV    333.1mV    381.4mV
2.85ns    377.2mV    309.9mV    217.5mV
3.57ns    127.7mV    215.4mV    18.42mV
4.455ns   17.92mV    98.41mV    4.64mV
6.245ns   2.193mV    8.689mV    1.406mV
19.95ns   840.7uV    678uV      1.03mV
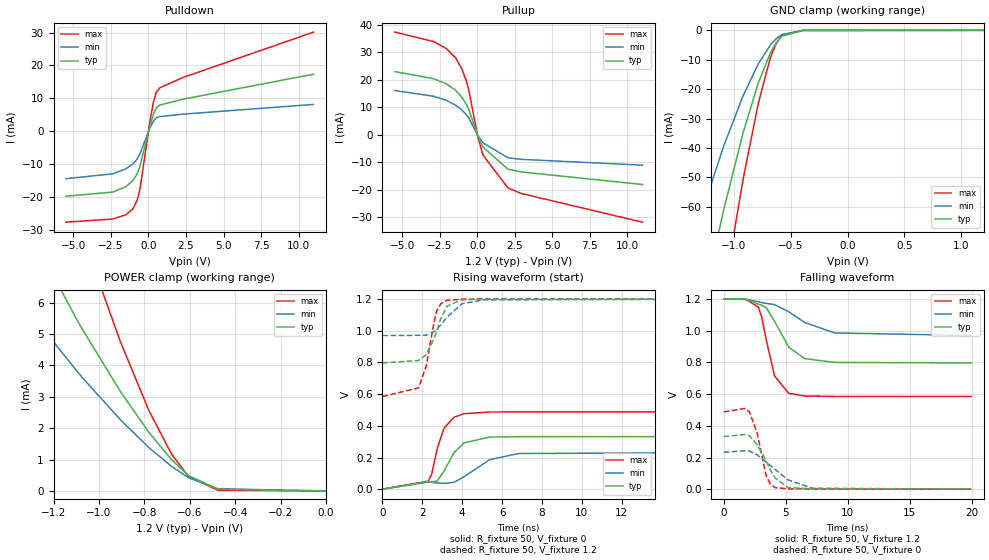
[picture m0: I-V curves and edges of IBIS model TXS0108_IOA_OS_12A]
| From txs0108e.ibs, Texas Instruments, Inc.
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[Model]   TXS0108_IOA_OS_12A
Model_type  I/O
Vinl=0.15
Vinh=1.0
Enable   Active-Low
Vref =   0
Rref =   1000000
Cref =   15p
Vmeas =   0.6
| variable   typ   min   max
C_comp   5.61pF   4.89pF   5.96pF
| C_pullup   6.13pF   4.57pF   7.30pF
| C_pulldown   6.48pF   5.52pF   7.61pF
| C_tri-state   5.61pF   4.89pF   5.96pF
[Temperature Range]   40   100   -40
| Ambient temperature   25   85   -40
[Voltage range]   1.2   1.2   1.2
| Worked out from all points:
|   slope of the pulldown table from 0 to 0.18 V, typ, clamps not added: 58.5 ohm
|   slope of the pullup table from 0 to 0.18 V, typ, clamps not added: 75.3 ohm
|   GND clamp passes 1 mA (typ) near -0.54 V on its own axis
|   POWER clamp passes 1 mA (typ) near -0.68 V on its own axis
|   rising waveform, R_fixture 50, V_fixture 0: 20-80 % time 952ps typ, 1.7ns min, 637ps max; typ from 0.001 V to 0.332 V
|   falling waveform, R_fixture 50, V_fixture 1.2: 20-80 % time 1.76ns typ, 2.84ns min, 1.04ns max; typ from 1.2 V to 0.797 V
|   rising waveform, R_fixture 50, V_fixture 1.2: 20-80 % time 727ps typ, 985ps min, 575ps max; typ from 0.797 V to 1.2 V
|   falling waveform, R_fixture 50, V_fixture 0: 20-80 % time 1.37ns typ, 2.24ns min, 803ps max; typ from 0.332 V to 0.001 V
[GND Clamp]
| TXS0108_IOA_OS_12A
|   Voltage   I(typ)   I(min)   I(max)
-5.5V     -1.162A    -886.7mA   -1.457A
-1.51V    -140.2mA   -92.9mA    -201.3mA
-1.465V   -130.9mA   -86.48mA   -188.6mA
-1.25V    -88.88mA   -57.92mA   -129.9mA
-1.09V    -60.8mA    -39.25mA   -89.36mA
-920mV    -34.79mA   -22.26mA   -50.61mA
-785mV    -17.76mA   -11.33mA   -24.59mA
-680mV    -7.68mA    -5.019mA   -9.327mA
-630mV    -4.288mA   -2.91mA    -4.593mA
-580mV    -2.011mA   -1.454mA   -1.795mA
-395mV    -28.25uA   -31.95uA   -8.3uA
1.2V      150.3pA    564.1pA    44.27pA
[POWER Clamp]
| TXS0108_IOA_OS_12A
|   Voltage   I(typ)   I(min)   I(max)
-5.5V     90.64mA    62.18mA    150.4mA
-1.575V   12.3mA     8.412mA    20.42mA
-1.54V    11.75mA    8.047mA    19.49mA
-1.31V    8.334mA    5.751mA    13.61mA
-1.1V     5.493mA    3.841mA    8.726mA
-1.07V    5.113mA    3.585mA    8.074mA
-905mV    3.161mA    2.264mA    4.744mA
-780mV    1.867mA    1.382mA    2.561mA
-680mV    992.7uA    780.1uA    1.172mA
-605mV    486.5uA    418.6uA    452uA
-475mV    55.47uA    68.05uA    20.74uA
0V        0A         0A         0A
[Pulldown]
| TXS0108_IOA_OS_12A
|   Voltage   I(typ)   I(min)   I(max)
-5.5V     -19.79mA   -14.45mA   -27.69mA
-2.385V   -18.53mA   -12.99mA   -26.72mA
-1.5V     -16.91mA   -11.45mA   -25.43mA
-1.035V   -15mA      -9.921mA   -23.63mA
-765mV    -13.07mA   -8.54mA    -21.12mA
-570mV    -10.78mA   -6.944mA   -17.78mA
95mV      1.659mA    999.1uA    2.901mA
330mV     5.154mA    3.047mA    8.854mA
525mV     7.077mA    4.069mA    11.89mA
750mV     7.96mA     4.44mA     13.16mA
2.29V     9.716mA    5.177mA    16.31mA
11V       17.33mA    8.131mA    30.14mA
[Pullup]
| TXS0108_IOA_OS_12A
|   Voltage   I(typ)   I(min)   I(max)
-5.5V     22.97mA    16.08mA    37.33mA
-2.905V   20.37mA    13.99mA    33.89mA
-2.065V   18.5mA     12.52mA    31.32mA
-1.455V   16.2mA     10.8mA     27.98mA
-1.035V   13.67mA    9.041mA    23.95mA
-690mV    10.64mA    6.989mA    18.83mA
-550mV    8.908mA    5.854mA    15.59mA
15mV      -214.7uA   -140.7uA   -372.6uA
375mV     -4.452mA   -2.938mA   -7.441mA
2.045V    -12.55mA   -8.379mA   -19.38mA
2.94V     -13.53mA   -8.942mA   -21.37mA
11V       -18.09mA   -11.06mA   -31.79mA
[Ramp]
| TXS0108_IOA_OS_12A
| variable   typ   min   max
dV/dt_r   0.20/9.57E-10   0.14/3.43E-09   0.29/6.37E-10
dV/dt_f   0.24/1.76E-09   0.14/2.84E-09   0.37/1.04E-09
R_load = 50
[Rising Waveform]
| TXS0108_IOA_OS_12A
R_fixture =   50
C_fixture =   0
L_fixture =   0
V_fixture =   0
V_fixture_min = 0
V_fixture_max = 0
|   Time   V(typ)   V(min)   V(max)
0s        716.1uV    603uV      841.3uV
2.305ns   46.98mV    45.64mV    51.29mV
2.475ns   46.12mV    44.05mV    98.31mV
2.755ns   52.9mV     39.3mV     260.2mV
3.09ns    115.3mV    36.99mV    385.7mV
3.59ns    231.2mV    43.92mV    454.5mV
4.09ns    292.6mV    78.66mV    476.5mV
5.375ns   329.3mV    186.6mV    487.3mV
6.83ns    332mV      225.5mV    488.1mV
19.95ns   332.3mV    232.8mV    488.3mV
[Falling Waveform]
| TXS0108_IOA_OS_12A
R_fixture =   50
C_fixture =   0
L_fixture =   0
V_fixture =   1.2
V_fixture_min = 1.2
V_fixture_max = 1.2
|   Time   V(typ)   V(min)   V(max)
0s        1.2V       1.2V       1.2V
1.785ns   1.199V     1.199V     1.198V
2.78ns    1.168V     1.183V     1.15V
3.055ns   1.161V     1.178V     1.088V
3.455ns   1.143V     1.172V     932.7mV
4.1ns     1.059V     1.165V     714.1mV
5.235ns   896.9mV    1.12V      605.2mV
6.525ns   824.3mV    1.052V     588.3mV
8.94ns    800.1mV    986.2mV    585.4mV
19.95ns   797.1mV    970mV      585.2mV
[Rising Waveform]
| TXS0108_IOA_OS_12A
R_fixture =   50
C_fixture =   0
L_fixture =   0
V_fixture =   1.2
V_fixture_min = 1.2
V_fixture_max = 1.2
|   Time   V(typ)   V(min)   V(max)
0s        797.1mV    970mV      585.2mV
1.81ns    812mV      971.2mV    639.4mV
2.195ns   848.5mV    971.9mV    776.9mV
2.605ns   955.2mV    995.4mV    1.065V
2.725ns   999.2mV    1.009V     1.126V
2.935ns   1.08V      1.038V     1.172V
3.245ns   1.156V     1.086V     1.192V
3.98ns    1.195V     1.17V      1.199V
5.07ns    1.2V       1.195V     1.2V
19.95ns   1.2V       1.2V       1.2V
[Falling Waveform]
| TXS0108_IOA_OS_12A
R_fixture =   50
C_fixture =   0
L_fixture =   0
V_fixture =   0
V_fixture_min = 0
V_fixture_max = 0
|   Time   V(typ)   V(min)   V(max)
0s        332.3mV    232.8mV    488.3mV
1.675ns   345.2mV    243.2mV    509.4mV
2.075ns   337.7mV    241.5mV    488.7mV
2.71ns    279.1mV    216.4mV    349.6mV
3.405ns   182.5mV    172.8mV    89.02mV
3.745ns   124.2mV    150.7mV    33.57mV
4.14ns    71.73mV    125.1mV    10.1mV
5.165ns   11.64mV    59.71mV    2.814mV
7.14ns    2.106mV    6.635mV    1.077mV
19.95ns   716.4uV    614.6uV    841.4uV
